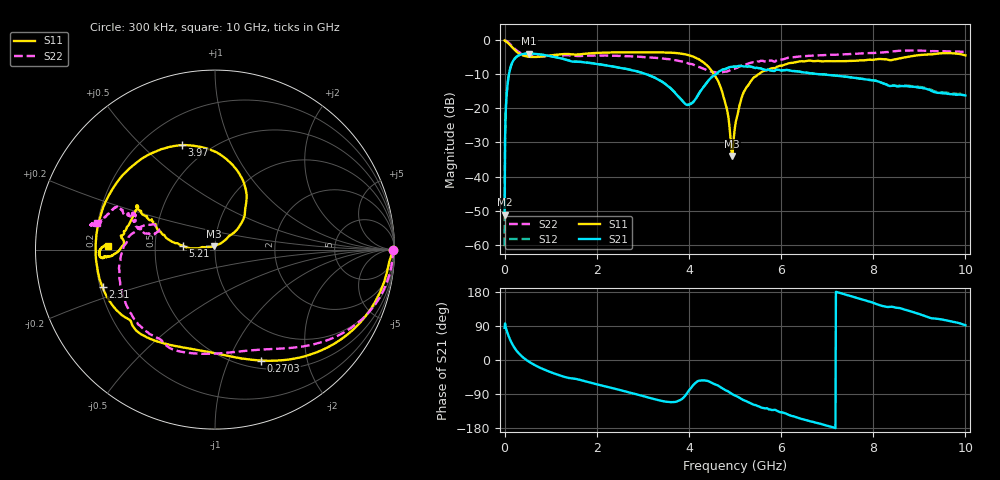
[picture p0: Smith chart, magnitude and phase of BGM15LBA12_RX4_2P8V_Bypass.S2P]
!Agilent Technologies,E5071C,MY46316587,B.13.01
!Date: Thu Dec 07 14:12:06 2017
!Data & Calibration Information:
!Freq	S11:SOLT2(ON)	S21:SOLT2(ON)	S12:SOLT2(ON)	S22:SOLT2(ON)
!PortZ  Port1:50+j0  Port2:50+j0
!Above PortZ is port z conversion or system Z0 setting when saving the data.
!When reading, reference impedance value at option line is always used.
# Hz S dB R 50
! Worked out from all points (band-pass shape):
!   1001 points, 300 kHz to 10 GHz, reference 50 ohm
!   highest |S21| = -3.91 dB at 530.3 MHz (marker M1); lowest = -51.2 dB at 300 kHz (marker M2)
!   |S21| within 3 dB of the highest: 155.5 MHz to 1.971 GHz (1.815 GHz wide, 171 % of centre)
!   lowest |S11| = -34.0 dB at 4.94 GHz (marker M3), VSWR 1.04, Z = 49.2 + j1.81 ohm
!   |S11| at or under -10 dB: 4.544 GHz to 5.509 GHz (965 MHz wide, 19.2 % of centre)
!   |S22| runs from -9.7 to -0.1 dB; largest |S21 - S12| = 0.0068
!   S11 on the Smith chart (normalised r, x): 300 kHz: open; 270.3 MHz: 0.59, -1.32; 2.31 GHz: 0.21, -0.16; 3.97 GHz: 0.36, +0.67; 5.21 GHz: 0.69, +0.03; 10 GHz: 0.25, +0.02
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300000  -0.07 -0.2  -51.19 84.8  -60.42 111.8  -0.07 0.0
6.02982e7  -0.64 -20.8  -13.42 72.0  -13.35 72.1  -0.39 -16.1
7.02979e7  -0.76 -24.0  -12.19 68.6  -12.14 68.6  -0.49 -18.5
1.402958e8  -1.74 -43.1  -7.47 48.2  -7.43 48.1  -1.42 -33.3
2.702919e8  -3.48 -67.4  -4.75 22.9  -4.74 22.8  -3.10 -51.3
5.302841e8  -4.86 -93.8  -3.91 -4.6  -3.90 -4.8  -4.57 -72.5
1.030269e9  -4.42 -121.2  -4.76 -33.5  -4.73 -33.7  -4.61 -100.3
1.67025e9  -4.08 -142.5  -6.39 -53.5  -6.34 -53.5  -4.61 -123.2
2.310231e9  -3.60 -161.6  -7.63 -73.4  -7.62 -73.2  -4.54 -138.8
3.3402e9  -3.56 152.8  -11.57 -106.0  -11.57 -105.6  -5.26 -167.2
3.970181e9  -4.29 107.6  -19.00 -85.5  -18.95 -85.4  -6.74 167.9
4.35017e9  -6.87 73.7  -13.15 -54.1  -13.10 -54.1  -8.56 157.8
4.630161e9  -11.87 49.5  -9.42 -67.2  -9.42 -67.3  -9.64 161.7
4.810156e9  -19.46 44.2  -8.36 -80.3  -8.34 -80.3  -9.20 164.8
4.940152e9  -33.98 113.4  -7.76 -90.0  -7.77 -90.1  -8.49 166.5
5.00015e9  -25.43 165.4  -7.76 -93.8  -7.74 -93.8  -8.31 166.7
5.090147e9  -19.53 176.5  -7.57 -99.5  -7.56 -99.6  -7.73 166.5
5.210144e9  -14.78 172.9  -7.71 -106.7  -7.71 -106.8  -7.36 164.6
5.610132e9  -9.09 158.9  -8.57 -126.7  -8.54 -126.8  -6.07 156.5
6.6701e9  -6.08 150.3  -9.77 -162.6  -9.73 -162.6  -4.54 156.5
8.34005e9  -5.80 174.1  -13.38 140.0  -13.32 139.9  -3.42 168.5
1e10  -4.45 177.9  -16.22 91.6  -15.96 92.1  -3.43 167.1
